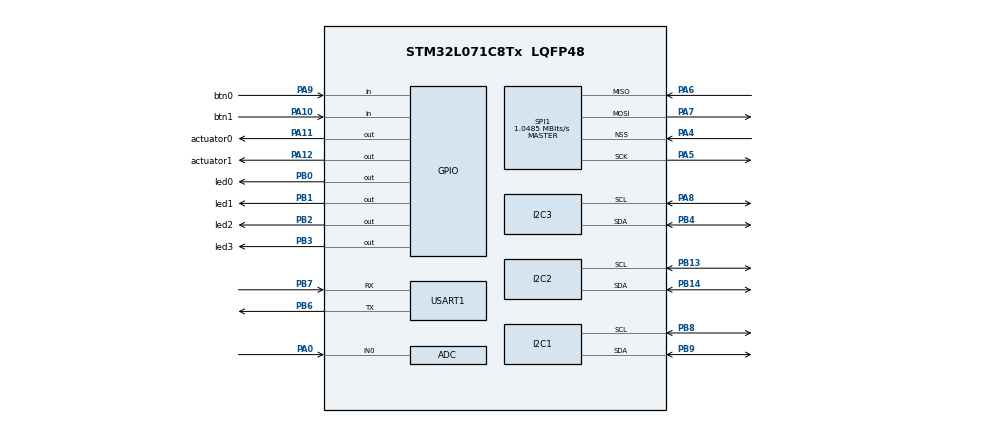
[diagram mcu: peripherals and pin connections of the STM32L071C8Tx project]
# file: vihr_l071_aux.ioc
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Mcu.Family=STM32L0
Mcu.Name=STM32L071C8Tx
Mcu.Package=LQFP48
PA0.Mode=IN0
PA0.Signal=ADC_IN0
PA10.GPIO_Label=btn1
PA10.Signal=GPIO_Input
PA11.GPIO_Label=actuator0
PA11.Signal=GPIO_Output
PA12.GPIO_Label=actuator1
PA12.Signal=GPIO_Output
PA13.Mode=Serial_Wire
PA13.Signal=SYS_SWDIO
PA14.Mode=Serial_Wire
PA14.Signal=SYS_SWCLK
PA4.Mode=NSS_Signal_Hard_Input
PA4.Signal=SPI1_NSS
PA5.Mode=Full_Duplex_Master
PA5.Signal=SPI1_SCK
PA6.Mode=Full_Duplex_Master
PA6.Signal=SPI1_MISO
PA7.Mode=Full_Duplex_Master
PA7.Signal=SPI1_MOSI
PA8.Mode=I2C
PA8.Signal=I2C3_SCL
PA9.GPIO_Label=btn0
PA9.Signal=GPIO_Input
PB0.GPIO_Label=led0
PB0.Signal=GPIO_Output
PB1.GPIO_Label=led1
PB1.Signal=GPIO_Output
PB13.Mode=I2C
PB13.Signal=I2C2_SCL
PB14.Mode=I2C
PB14.Signal=I2C2_SDA
PB2.GPIO_Label=led2
PB2.Signal=GPIO_Output
PB3.GPIO_Label=led3
PB3.Signal=GPIO_Output
PB4.Mode=I2C
PB4.Signal=I2C3_SDA
PB6.Mode=Asynchronous
PB6.Signal=USART1_TX
PB7.Mode=Asynchronous
PB7.Signal=USART1_RX
PB8.Mode=I2C
PB8.Signal=I2C1_SCL
PB9.Mode=I2C
PB9.Signal=I2C1_SDA
ProjectManager.HeapSize=0x200
ProjectManager.StackSize=0x400
ProjectManager.TargetToolchain=Makefile
RCC.AHBFreq_Value=2097000
RCC.APB1Freq_Value=2097000
RCC.APB1TimFreq_Value=2097000
RCC.APB2Freq_Value=2097000
RCC.APB2TimFreq_Value=2097000
RCC.HSE_VALUE=8000000
RCC.HSI16_VALUE=16000000
RCC.HSI_VALUE=16000000
RCC.LSE_VALUE=32768
RCC.MSI_VALUE=2097000
RCC.SYSCLKFreq_VALUE=2097000
RCC.VCOOutputFreq_Value=48000000
SPI1.CalculateBaudRate=1.0485 MBits/s
SPI1.Direction=SPI_DIRECTION_2LINES
SPI1.Mode=SPI_MODE_MASTER
SPI1.VirtualNSS=VM_NSSHARD
SPI1.VirtualType=VM_MASTER
USART1.VirtualMode-Asynchronous=VM_ASYNC
board=custom

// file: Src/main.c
/**
  ******************************************************************************
  * @file           : main.c
  * @brief          : Main program body
  ******************************************************************************
  ** This notice applies to any and all portions of this file
  * that are not between comment pairs USER CODE BEGIN and
  * USER CODE END. Other portions of this file, whether
  * inserted by the user or by software development tools
  * are owned by their respective copyright owners.
  *
  * COPYRIGHT(c) 2019 STMicroelectronics
  *
  * Redistribution and use in source and binary forms, with or without modification,
  * are permitted provided that the following conditions are met:
  *   1. Redistributions of source code must retain the above copyright notice,
  *      this list of conditions and the following disclaimer.
  *   2. Redistributions in binary form must reproduce the above copyright notice,
  *      this list of conditions and the following disclaimer in the documentation
  *      and/or other materials provided with the distribution.
  *   3. Neither the name of STMicroelectronics nor the names of its contributors
  *      may be used to endorse or promote products derived from this software
  *      without specific prior written permission.
  *
  * THIS SOFTWARE IS PROVIDED BY THE COPYRIGHT HOLDERS AND CONTRIBUTORS "AS IS"
  * AND ANY EXPRESS OR IMPLIED WARRANTIES, INCLUDING, BUT NOT LIMITED TO, THE
  * IMPLIED WARRANTIES OF MERCHANTABILITY AND FITNESS FOR A PARTICULAR PURPOSE ARE
  * DISCLAIMED. IN NO EVENT SHALL THE COPYRIGHT HOLDER OR CONTRIBUTORS BE LIABLE
  * FOR ANY DIRECT, INDIRECT, INCIDENTAL, SPECIAL, EXEMPLARY, OR CONSEQUENTIAL
  * DAMAGES (INCLUDING, BUT NOT LIMITED TO, PROCUREMENT OF SUBSTITUTE GOODS OR
  * SERVICES; LOSS OF USE, DATA, OR PROFITS; OR BUSINESS INTERRUPTION) HOWEVER
  * CAUSED AND ON ANY THEORY OF LIABILITY, WHETHER IN CONTRACT, STRICT LIABILITY,
  * OR TORT (INCLUDING NEGLIGENCE OR OTHERWISE) ARISING IN ANY WAY OUT OF THE USE
  * OF THIS SOFTWARE, EVEN IF ADVISED OF THE POSSIBILITY OF SUCH DAMAGE.
  *
  ******************************************************************************
  */
#include "main.h"
#include "string.h"
#include "stdio.h"
#include "stm32l0xx_hal.h"
#include "adc.h"
#include "i2c.h"
#include "spi.h"
#include "tim.h"
#include "usart.h"
#include "gpio.h"

#include "ssd1306.h"

#include "one_second_timer_interface.h"
#include "pressure_sensor_object.h"
#include "voltmeter_object.h"
#include "depth_switch_interface.h"
#include "rtc_ds3231_interface.h"
#include "at24c32_interface.h"
#include "atm_barometer_interface.h"
#include "dive_meter_interface.h"

/* USER CODE BEGIN PV */

static char message[256];
static char timestamp[64];

void SystemClock_Config(void);

uint8_t primitive_delay()
{
	uint32_t volatile i;
	for(i=0; i<300000; i++);

	return 0;
}

//%%%%%%%%%%%%%%%%%%%%%%%%%%%%%%%%%%%%%%%%%%%%%%%%%%%%%%%%%%%%%%%%%%%%%%%%%%%%%
//%%%%%%%%%%%%%%%%%%%%%%%%%%%%%%%%%%%%%%%%%%%%%%%%%%%%%%%%%%%%%%%%%%%%%%%%%%%%%
//%%%%%%%%%%%%%%%%%%%%%%%%%%%%%%%%%%%%%%%%%%%%%%%%%%%%%%%%%%%%%%%%%%%%%%%%%%%%%
//%%%%%%%%%%%%%%%%%%%%%%%%%%%%%%%%%%%%%%%%%%%%%%%%%%%%%%%%%%%%%%%%%%%%%%%%%%%%%
//%%%%%%%%%%%%%%%%%%%%%%%%%%%%%%%%%%%%%%%%%%%%%%%%%%%%%%%%%%%%%%%%%%%%%%%%%%%%%
//%%%%%%%%%%%%%%%%%%%%%%%%%%%%%%%%%%%%%%%%%%%%%%%%%%%%%%%%%%%%%%%%%%%%%%%%%%%%%
//%%%%%%%%%%%%%%%%%%%%%%%%%%%%%%%%%%%%%%%%%%%%%%%%%%%%%%%%%%%%%%%%%%%%%%%%%%%%%
//%%%%%%%%%%%%%%%%%%%%%%%%%%%%%%%%%%%%%%%%%%%%%%%%%%%%%%%%%%%%%%%%%%%%%%%%%%%%%
//%%%%%%%%%%%%%%%%%%%%%%%%%%%%%%%%%%%%%%%%%%%%%%%%%%%%%%%%%%%%%%%%%%%%%%%%%%%%%
//%%%%%%%%%%%%%%%%%%%%%%%%%%%%%%%%%%%%%%%%%%%%%%%%%%%%%%%%%%%%%%%%%%%%%%%%%%%%%
//%%%%%%%%%%%%%%%%%%%%%%%%%%%%%%%%%%%%%%%%%%%%%%%%%%%%%%%%%%%%%%%%%%%%%%%%%%%%%
int main(void)
{

	uint32_t seconds_in_minute = 60;
	uint32_t seconds_in_hour = seconds_in_minute * 60;
	uint32_t seconds_in_day = seconds_in_hour * 24;
	uint32_t rtc_time_counter;

	/* Reset of all peripherals, Initializes the Flash interface and the Systick. */
    HAL_Init();

    /* Configure the system clock */
    SystemClock_Config();

    /* Initialize all configured peripherals */
    MX_GPIO_Init();
    MX_ADC_Init();
    MX_I2C1_Init();
    MX_I2C2_Init();
    MX_I2C3_Init();
    MX_SPI1_Init();
    // enable spi1
    SPI1->CR1 |= SPI_CR1_SPE;
    MX_USART1_UART_Init();

	//--------init display1------------------------------
    ssd1306_set_i2c_port(&hi2c1, 1);
  	ssd1306_Init();
  	HAL_Delay(100);
  	ssd1306_Fill(White);
  	ssd1306_UpdateScreen();
  	HAL_Delay(100);
  	ssd1306_Fill(Black);
  	ssd1306_UpdateScreen();

  	HAL_Delay(100);

  	ssd1306_SetCursor(0,0);
  	ssd1306_WriteString("DiveCmp", Font_16x26, White);
  	ssd1306_SetCursor(0,30);
  	ssd1306_WriteString("Start..", Font_16x26, White);
  	ssd1306_UpdateScreen();

	one_second_timer_init();
	one_second_timer_start();

	pressure_sensor_object_init();
	HAL_Delay(1000);

	int odd_even = 0;

//#define DEBUG

	//************************   MAIN LOOP   *********************************

#ifdef DEBUG

	int led_counter = 0;

	while(1)
	{

		// debug
		//*
	    HAL_GPIO_TogglePin(led0_GPIO_Port, led3_Pin); //
	    //HAL_Delay(500);
		primitive_delay();
	    HAL_GPIO_TogglePin(led0_GPIO_Port, led3_Pin); //
	    //HAL_Delay(500);
		primitive_delay();
		//*/

		/*
		if(one_second_timer_get_flag())
		{
			one_second_timer_reset_flag();
			odd_even = (odd_even+1)%2;

			pressure_sensor_measure_pressure_temperature();
		    double P = pressure_sensor_get_pressure();
		    double actual_temperature = pressure_sensor_get_temperature();

			led_counter++;
			depth_switch_turn_signal_led(led_counter);
			if(led_counter == 5)
				led_counter = 0;

		}
		*/

	}

#endif

#ifndef DEBUG

	depth_switch_turn_signal_led(1);

	uint32_t surface_pressure = 101325;
	ssd1306_Fill(Black);

	while(1)
	{

		if(one_second_timer_get_flag())
		{
			one_second_timer_reset_flag();
			odd_even = (odd_even+1)%2;

			pressure_sensor_measure_pressure_temperature();
		    //double P = pressure_sensor_get_pressure();
		    //double actual_temperature = pressure_sensor_get_temperature();

			voltmeter_measure_voltage();
		    //double accu_voltage = voltmeter_get_voltage();
		    double accu_percentage = voltmeter_get_percentage();

			// debug
			//*
			//ssd1306_Fill(Black);
  		    ssd1306_SetCursor(3,30);
			if(odd_even)
		        sprintf(message, "P%05d:T%03d" , (int)(P/10), (int)(actual_temperature/10));
			else
		        sprintf(message, "P%05d T%03d" , (int)(P/10), (int)(actual_temperature/10));
  		    ssd1306_WriteString(message, Font_11x18, White);
  		    ssd1306_WriteString(message, Font_11x18, White);
  		    ssd1306_UpdateScreen();
			//*/

  		    ssd1306_SetCursor(0,0);
		    sprintf(message, "akkum %02d%%", (int)accu_percentage);
  		    ssd1306_WriteString(message, Font_11x18, White);
  		    ssd1306_UpdateScreen();
		}

  	}// end while(1)

#endif

}
//%%%%%%%%%%%%%%%%%%%%%%%%%%%%%%%%%%%%%%%%%%%%%%%%%%%%%%%%%%%%%%%%%%%%%%%%%%%%%
//%%%%%%%%%%%%%%%%%%%%%%%%%%%%%%%%%%%%%%%%%%%%%%%%%%%%%%%%%%%%%%%%%%%%%%%%%%%%%
//%%%%%%%%%%%%%%%%%%%%%%%%%%%%%%%%%%%%%%%%%%%%%%%%%%%%%%%%%%%%%%%%%%%%%%%%%%%%%
//%%%%%%%%%%%%%%%%%%%%%%%%%%%%%%%%%%%%%%%%%%%%%%%%%%%%%%%%%%%%%%%%%%%%%%%%%%%%%
//%%%%%%%%%%%%%%%%%%%%%%%%%%%%%%%%%%%%%%%%%%%%%%%%%%%%%%%%%%%%%%%%%%%%%%%%%%%%%
//%%%%%%%%%%%%%%%%%%%%%%%%%%%%%%%%%%%%%%%%%%%%%%%%%%%%%%%%%%%%%%%%%%%%%%%%%%%%%
//%%%%%%%%%%%%%%%%%%%%%%%%%%%%%%%%%%%%%%%%%%%%%%%%%%%%%%%%%%%%%%%%%%%%%%%%%%%%%
//%%%%%%%%%%%%%%%%%%%%%%%%%%%%%%%%%%%%%%%%%%%%%%%%%%%%%%%%%%%%%%%%%%%%%%%%%%%%%
//%%%%%%%%%%%%%%%%%%%%%%%%%%%%%%%%%%%%%%%%%%%%%%%%%%%%%%%%%%%%%%%%%%%%%%%%%%%%%
//%%%%%%%%%%%%%%%%%%%%%%%%%%%%%%%%%%%%%%%%%%%%%%%%%%%%%%%%%%%%%%%%%%%%%%%%%%%%%
//%%%%%%%%%%%%%%%%%%%%%%%%%%%%%%%%%%%%%%%%%%%%%%%%%%%%%%%%%%%%%%%%%%%%%%%%%%%%%

void SystemClock_Config(void)
{

  RCC_OscInitTypeDef RCC_OscInitStruct;
  RCC_ClkInitTypeDef RCC_ClkInitStruct;
  RCC_PeriphCLKInitTypeDef PeriphClkInit;

    /**Configure the main internal regulator output voltage
    */
  __HAL_PWR_VOLTAGESCALING_CONFIG(PWR_REGULATOR_VOLTAGE_SCALE1);

    /**Initializes the CPU, AHB and APB busses clocks
    */
  RCC_OscInitStruct.OscillatorType = RCC_OSCILLATORTYPE_HSI;
  RCC_OscInitStruct.HSIState = RCC_HSI_ON;
  RCC_OscInitStruct.HSICalibrationValue = 16;
  RCC_OscInitStruct.PLL.PLLState = RCC_PLL_ON;
  RCC_OscInitStruct.PLL.PLLSource = RCC_PLLSOURCE_HSI;
  RCC_OscInitStruct.PLL.PLLMUL = RCC_PLLMUL_3;
  RCC_OscInitStruct.PLL.PLLDIV = RCC_PLLDIV_3;
  if (HAL_RCC_OscConfig(&RCC_OscInitStruct) != HAL_OK)
  {
    _Error_Handler(__FILE__, __LINE__);
  }

    /**Initializes the CPU, AHB and APB busses clocks
    */
  RCC_ClkInitStruct.ClockType = RCC_CLOCKTYPE_HCLK|RCC_CLOCKTYPE_SYSCLK
                              |RCC_CLOCKTYPE_PCLK1|RCC_CLOCKTYPE_PCLK2;
  RCC_ClkInitStruct.SYSCLKSource = RCC_SYSCLKSOURCE_PLLCLK;
  RCC_ClkInitStruct.AHBCLKDivider = RCC_SYSCLK_DIV8;
  RCC_ClkInitStruct.APB1CLKDivider = RCC_HCLK_DIV1;
  RCC_ClkInitStruct.APB2CLKDivider = RCC_HCLK_DIV1;

  if (HAL_RCC_ClockConfig(&RCC_ClkInitStruct, FLASH_LATENCY_0) != HAL_OK)
  {
    _Error_Handler(__FILE__, __LINE__);
  }

  PeriphClkInit.PeriphClockSelection = RCC_PERIPHCLK_USART1|RCC_PERIPHCLK_I2C1
                              |RCC_PERIPHCLK_I2C3;
  PeriphClkInit.Usart1ClockSelection = RCC_USART1CLKSOURCE_PCLK2;
  PeriphClkInit.I2c1ClockSelection = RCC_I2C1CLKSOURCE_PCLK1;
  PeriphClkInit.I2c3ClockSelection = RCC_I2C3CLKSOURCE_PCLK1;
  if (HAL_RCCEx_PeriphCLKConfig(&PeriphClkInit) != HAL_OK)
  {
    _Error_Handler(__FILE__, __LINE__);
  }

    /**Configure the Systick interrupt time
    */
  //HAL_SYSTICK_Config(HAL_RCC_GetHCLKFreq()/1000);

    /**Configure the Systick
    */
  //HAL_SYSTICK_CLKSourceConfig(SYSTICK_CLKSOURCE_HCLK);

  /* SysTick_IRQn interrupt configuration */
  //HAL_NVIC_SetPriority(SysTick_IRQn, 0, 0);
}

void _Error_Handler(char *file, int line)
{
  while(1)
  {
  }
}

/************************ (C) COPYRIGHT STMicroelectronics *****END OF FILE****/
